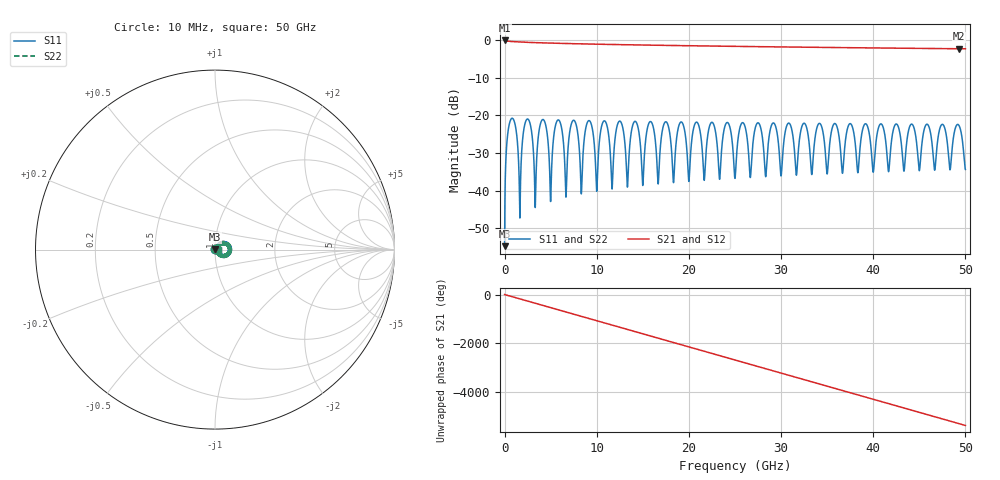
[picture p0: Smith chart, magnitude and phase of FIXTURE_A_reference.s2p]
! Reference exacte : Fixture A synthetique : ligne Zc=55.0 ohm, delai=300 ps, pertes 1.0 dB @10 GHz (~sqrt(f)), eps_r_eff=3.0 -> 51.93 mm, Z0=50 ohm
! Frequency(Hz) S11 S21 S12 S22 (Re Im)
# Hz S RI R 50
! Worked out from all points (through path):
!   5000 points, 10 MHz to 50 GHz, reference 50 ohm
!   highest |S21| = -0.03 dB at 10 MHz (marker M1); lowest = -2.3 dB at 49.31 GHz (marker M2)
!   group delay of S21, straight-line fit = 300 ps
!   lowest |S11| = -54.8 dB at 10 MHz (marker M3), VSWR 1.00, Z = 50 + j0.179 ohm
!   |S11| at or under -10 dB: start of sweep to end of sweep
!   |S22| runs from -54.8 to -20.7 dB; largest |S21 - S12| = 0
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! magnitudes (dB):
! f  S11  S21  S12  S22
! 10 MHz  -54.8  0.0  0.0  -54.8
! 790 MHz  -20.7  -0.3  -0.3  -20.7
! 1.65 GHz  -45.8  -0.4  -0.4  -45.8
! 2.49 GHz  -20.9  -0.5  -0.5  -20.9
! 3.32 GHz  -44.0  -0.6  -0.6  -44.0
! 4.16 GHz  -21.1  -0.7  -0.7  -21.1
! 4.98 GHz  -42.1  -0.7  -0.7  -42.1
! 5.83 GHz  -21.2  -0.8  -0.8  -21.2
! 8.35 GHz  -40.5  -0.9  -0.9  -40.5
! 9.16 GHz  -21.3  -1.0  -1.0  -21.3
! 9.99 GHz  -40.1  -1.0  -1.0  -40.1
! 10.83 GHz  -21.4  -1.1  -1.1  -21.4
! 11.65 GHz  -39.3  -1.1  -1.1  -39.3
! 12.5 GHz  -21.5  -1.2  -1.2  -21.5
! 16.68 GHz  -38.1  -1.3  -1.3  -38.1
! 17.5 GHz  -21.7  -1.4  -1.4  -21.7
! 25.01 GHz  -36.7  -1.6  -1.6  -36.7
! 25.83 GHz  -21.9  -1.6  -1.6  -21.9
! 33.34 GHz  -35.7  -1.8  -1.8  -35.7
! 41.67 GHz  -34.9  -2.0  -2.0  -34.9
! 49.31 GHz  -22.7  -2.3  -2.3  -22.7
! 50 GHz  -34.3  -2.2  -2.2  -34.3
